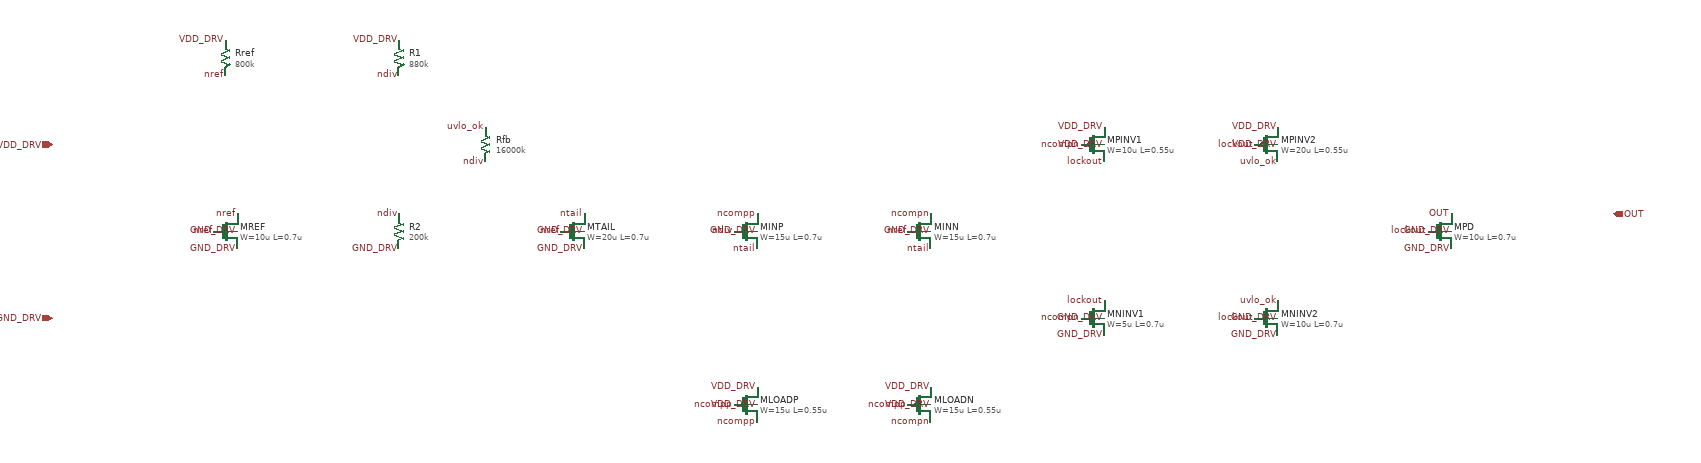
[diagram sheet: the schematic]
v {xschem version=3.4.7 file_version=1.2

* uvlo -- drive-rail undervoltage-lockout comparator/reference sub-cell
* (issue #220, spec/gate-driver.md Sec.5; parameters ratified by
* spec/decision-records/0001-block-interface-and-uvlo-parameters.md
* Decisions 4-5). Actual measured PVT numbers against those targets are
* recorded in spec/decision-records/0018-uvlo-comparator-pvt-measurement.md
* and sim/uvlo-trip-verification/records/ -- read that record before
* assuming the typ numbers below hold at every corner; they do not.
*
* Topology, exactly as decision record 0001 Decision 5 specifies: a
* resistive divider off VDD_DRV (R1/R2) compared against a diode-connected
* 6V0-corner NMOS Vt reference (XMREF), both built from nfet_06v0/pfet_06v0
* only -- no bandgap, no thin-oxide device (spec Sec.2.5, drive-rail
* domain; this cell has no VDD_LOGIC/GND_LOGIC pins at all, consistent with
* decision record 0001 Decision 5's "only VDD_DRV is monitored").
*
* Ports:
*   VDD_DRV -- 5V nominal / 6V stretch drive rail (block VDD_DRV)
*   GND_DRV -- drive rail return (block GND_DRV)
*   OUT     -- block OUT net (shared with output_stage's OUT, decision
*              record 0001 Decision 5) -- this cell actively pulls OUT low
*              (XMPD, a large nfet_06v0) whenever VDD_DRV is below the
*              rising threshold / above the falling threshold has not yet
*              been crossed, i.e. during lockout, overriding IN
*              unconditionally (XMPD's gate is driven only by this cell's
*              own comparator chain, never by IN or IN_DRV).
*
* Signal path:
*   Reference:  VDD_DRV -[Rref]-> nref -[XMREF diode-connected]-> GND_DRV
*   Divider:    VDD_DRV -[R1]-> ndiv -[R2]-> GND_DRV, with a positive-
*               feedback resistor Rfb from the buffered digital output
*               uvlo_ok back onto ndiv -- this is what creates the
*               hysteresis: Rfb effectively lowers the divider's top
*               resistance (R1||Rfb) while uvlo_ok is high (released),
*               raising ndiv for a given VDD_DRV and so requiring VDD_DRV
*               to fall further before ndiv drops back below nref (falling
*               threshold below rising threshold, matching decision record
*               0001 Decision 4's hysteresis direction). See
*               design/uvlo-comparator-sizing.md for the full derivation
*               and the measured tuning iterations.
*   Comparator: XMTAIL (current-mirrors off nref) biases a 5T differential
*               pair (XMINP/XMINN, thin... no, nfet_06v0, gates on
*               ndiv/nref) loaded by a pfet_06v0 current mirror
*               (XMLOADP/XMLOADN); ncompn is the single-ended output,
*               HIGH when ndiv > nref (VDD_DRV above the trip point).
*   Buffer:     ncompn -> INV1 (XMPINV1/XMNINV1) -> lockout (active-HIGH
*               pulldown-enable signal, HIGH during lockout) -> INV2
*               (XMPINV2/XMNINV2) -> uvlo_ok (active-HIGH "released"
*               status, drives Rfb).
*   Output:     XMPD, gate=lockout, drain=OUT, source=GND_DRV -- W=10u,
*               m=800 (effective 8000u), sized to dominate over
*               output_stage's own final push-pull stage (MP6, W=10u
*               m=500, design/output_stage.sch) so OUT is actively held
*               low regardless of what output_stage's own drive is doing.
*
* Generated by hand per xschem text format (same convention as
* design/level_shifter.sch / design/output_stage.sch), net connectivity
* verified via `xschem -x -n -s` (see PR description).
}
G {}
K {}
V {}
S {}
E {}

* --- reference generator: Rref + diode-connected XMREF ---
C {devices/res.sym} 0 -300 0 0 {name=Rref value=800k footprint=1206 device=resistor m=1}
C {devices/lab_pin.sym} 0 -330 0 0 {name=l1 lab=VDD_DRV}
C {devices/lab_pin.sym} 0 -270 0 0 {name=l2 lab=nref}
C {symbols/nfet_06v0.sym} 0 0 0 0 {name=MREF
L=0.7u
W=10u
nf=1
m=1
ad="'int((nf+1)/2) * W/nf * 0.18u'"
pd="'2*int((nf+1)/2) * (W/nf + 0.18u)'"
as="'int((nf+2)/2) * W/nf * 0.18u'"
ps="'2*int((nf+2)/2) * (W/nf + 0.18u)'"
nrd="'0.18u / W'" nrs="'0.18u / W'"
sa=0 sb=0 sd=0
model=nfet_06v0
spiceprefix=X
}
C {devices/lab_pin.sym} 20 -30 0 0 {name=l3 lab=nref}
C {devices/lab_pin.sym} -20 0 0 0 {name=l4 lab=nref}
C {devices/lab_pin.sym} 20 30 0 0 {name=l5 lab=GND_DRV}
C {devices/lab_pin.sym} 20 0 0 0 {name=l6 lab=GND_DRV}

* --- resistive divider with hysteresis feedback ---
C {devices/res.sym} 300 -300 0 0 {name=R1 value=880k footprint=1206 device=resistor m=1}
C {devices/lab_pin.sym} 300 -330 0 0 {name=l7 lab=VDD_DRV}
C {devices/lab_pin.sym} 300 -270 0 0 {name=l8 lab=ndiv}
C {devices/res.sym} 300 0 0 0 {name=R2 value=200k footprint=1206 device=resistor m=1}
C {devices/lab_pin.sym} 300 -30 0 0 {name=l9 lab=ndiv}
C {devices/lab_pin.sym} 300 30 0 0 {name=l10 lab=GND_DRV}
C {devices/res.sym} 450 -150 0 0 {name=Rfb value=16000k footprint=1206 device=resistor m=1}
C {devices/lab_pin.sym} 450 -180 0 0 {name=l11 lab=uvlo_ok}
C {devices/lab_pin.sym} 450 -120 0 0 {name=l12 lab=ndiv}

* --- tail current mirror (mirrors XMREF's bias current off nref) ---
C {symbols/nfet_06v0.sym} 600 0 0 0 {name=MTAIL
L=0.7u
W=20u
nf=1
m=1
ad="'int((nf+1)/2) * W/nf * 0.18u'"
pd="'2*int((nf+1)/2) * (W/nf + 0.18u)'"
as="'int((nf+2)/2) * W/nf * 0.18u'"
ps="'2*int((nf+2)/2) * (W/nf + 0.18u)'"
nrd="'0.18u / W'" nrs="'0.18u / W'"
sa=0 sb=0 sd=0
model=nfet_06v0
spiceprefix=X
}
C {devices/lab_pin.sym} 620 -30 0 0 {name=l13 lab=ntail}
C {devices/lab_pin.sym} 580 0 0 0 {name=l14 lab=nref}
C {devices/lab_pin.sym} 620 30 0 0 {name=l15 lab=GND_DRV}
C {devices/lab_pin.sym} 620 0 0 0 {name=l16 lab=GND_DRV}

* --- differential pair: ndiv (+) vs nref (-) ---
C {symbols/nfet_06v0.sym} 900 0 0 0 {name=MINP
L=0.7u
W=15u
nf=1
m=1
ad="'int((nf+1)/2) * W/nf * 0.18u'"
pd="'2*int((nf+1)/2) * (W/nf + 0.18u)'"
as="'int((nf+2)/2) * W/nf * 0.18u'"
ps="'2*int((nf+2)/2) * (W/nf + 0.18u)'"
nrd="'0.18u / W'" nrs="'0.18u / W'"
sa=0 sb=0 sd=0
model=nfet_06v0
spiceprefix=X
}
C {devices/lab_pin.sym} 920 -30 0 0 {name=l17 lab=ncompp}
C {devices/lab_pin.sym} 880 0 0 0 {name=l18 lab=ndiv}
C {devices/lab_pin.sym} 920 30 0 0 {name=l19 lab=ntail}
C {devices/lab_pin.sym} 920 0 0 0 {name=l20 lab=GND_DRV}
C {symbols/nfet_06v0.sym} 1200 0 0 0 {name=MINN
L=0.7u
W=15u
nf=1
m=1
ad="'int((nf+1)/2) * W/nf * 0.18u'"
pd="'2*int((nf+1)/2) * (W/nf + 0.18u)'"
as="'int((nf+2)/2) * W/nf * 0.18u'"
ps="'2*int((nf+2)/2) * (W/nf + 0.18u)'"
nrd="'0.18u / W'" nrs="'0.18u / W'"
sa=0 sb=0 sd=0
model=nfet_06v0
spiceprefix=X
}
C {devices/lab_pin.sym} 1220 -30 0 0 {name=l21 lab=ncompn}
C {devices/lab_pin.sym} 1180 0 0 0 {name=l22 lab=nref}
C {devices/lab_pin.sym} 1220 30 0 0 {name=l23 lab=ntail}
C {devices/lab_pin.sym} 1220 0 0 0 {name=l24 lab=GND_DRV}

* --- pfet current-mirror load ---
C {symbols/pfet_06v0.sym} 900 300 0 0 {name=MLOADP
L=0.55u
W=15u
nf=1
m=1
ad="'int((nf+1)/2) * W/nf * 0.18u'"
pd="'2*int((nf+1)/2) * (W/nf + 0.18u)'"
as="'int((nf+2)/2) * W/nf * 0.18u'"
ps="'2*int((nf+2)/2) * (W/nf + 0.18u)'"
nrd="'0.18u / W'" nrs="'0.18u / W'"
sa=0 sb=0 sd=0
model=pfet_06v0
spiceprefix=X
}
C {devices/lab_pin.sym} 920 330 0 0 {name=l25 lab=ncompp}
C {devices/lab_pin.sym} 880 300 0 0 {name=l26 lab=ncompp}
C {devices/lab_pin.sym} 920 270 0 0 {name=l27 lab=VDD_DRV}
C {devices/lab_pin.sym} 920 300 0 0 {name=l28 lab=VDD_DRV}
C {symbols/pfet_06v0.sym} 1200 300 0 0 {name=MLOADN
L=0.55u
W=15u
nf=1
m=1
ad="'int((nf+1)/2) * W/nf * 0.18u'"
pd="'2*int((nf+1)/2) * (W/nf + 0.18u)'"
as="'int((nf+2)/2) * W/nf * 0.18u'"
ps="'2*int((nf+2)/2) * (W/nf + 0.18u)'"
nrd="'0.18u / W'" nrs="'0.18u / W'"
sa=0 sb=0 sd=0
model=pfet_06v0
spiceprefix=X
}
C {devices/lab_pin.sym} 1220 330 0 0 {name=l29 lab=ncompn}
C {devices/lab_pin.sym} 1180 300 0 0 {name=l30 lab=ncompp}
C {devices/lab_pin.sym} 1220 270 0 0 {name=l31 lab=VDD_DRV}
C {devices/lab_pin.sym} 1220 300 0 0 {name=l32 lab=VDD_DRV}

* --- buffer stage 1: ncompn -> lockout (active-high pulldown-enable) ---
C {symbols/pfet_06v0.sym} 1500 -150 0 0 {name=MPINV1
L=0.55u
W=10u
nf=1
m=1
ad="'int((nf+1)/2) * W/nf * 0.18u'"
pd="'2*int((nf+1)/2) * (W/nf + 0.18u)'"
as="'int((nf+2)/2) * W/nf * 0.18u'"
ps="'2*int((nf+2)/2) * (W/nf + 0.18u)'"
nrd="'0.18u / W'" nrs="'0.18u / W'"
sa=0 sb=0 sd=0
model=pfet_06v0
spiceprefix=X
}
C {devices/lab_pin.sym} 1520 -120 0 0 {name=l33 lab=lockout}
C {devices/lab_pin.sym} 1480 -150 0 0 {name=l34 lab=ncompn}
C {devices/lab_pin.sym} 1520 -180 0 0 {name=l35 lab=VDD_DRV}
C {devices/lab_pin.sym} 1520 -150 0 0 {name=l36 lab=VDD_DRV}
C {symbols/nfet_06v0.sym} 1500 150 0 0 {name=MNINV1
L=0.7u
W=5u
nf=1
m=1
ad="'int((nf+1)/2) * W/nf * 0.18u'"
pd="'2*int((nf+1)/2) * (W/nf + 0.18u)'"
as="'int((nf+2)/2) * W/nf * 0.18u'"
ps="'2*int((nf+2)/2) * (W/nf + 0.18u)'"
nrd="'0.18u / W'" nrs="'0.18u / W'"
sa=0 sb=0 sd=0
model=nfet_06v0
spiceprefix=X
}
C {devices/lab_pin.sym} 1520 120 0 0 {name=l37 lab=lockout}
C {devices/lab_pin.sym} 1480 150 0 0 {name=l38 lab=ncompn}
C {devices/lab_pin.sym} 1520 180 0 0 {name=l39 lab=GND_DRV}
C {devices/lab_pin.sym} 1520 150 0 0 {name=l40 lab=GND_DRV}

* --- buffer stage 2: lockout -> uvlo_ok (drives Rfb) ---
C {symbols/pfet_06v0.sym} 1800 -150 0 0 {name=MPINV2
L=0.55u
W=20u
nf=1
m=1
ad="'int((nf+1)/2) * W/nf * 0.18u'"
pd="'2*int((nf+1)/2) * (W/nf + 0.18u)'"
as="'int((nf+2)/2) * W/nf * 0.18u'"
ps="'2*int((nf+2)/2) * (W/nf + 0.18u)'"
nrd="'0.18u / W'" nrs="'0.18u / W'"
sa=0 sb=0 sd=0
model=pfet_06v0
spiceprefix=X
}
C {devices/lab_pin.sym} 1820 -120 0 0 {name=l41 lab=uvlo_ok}
C {devices/lab_pin.sym} 1780 -150 0 0 {name=l42 lab=lockout}
C {devices/lab_pin.sym} 1820 -180 0 0 {name=l43 lab=VDD_DRV}
C {devices/lab_pin.sym} 1820 -150 0 0 {name=l44 lab=VDD_DRV}
C {symbols/nfet_06v0.sym} 1800 150 0 0 {name=MNINV2
L=0.7u
W=10u
nf=1
m=1
ad="'int((nf+1)/2) * W/nf * 0.18u'"
pd="'2*int((nf+1)/2) * (W/nf + 0.18u)'"
as="'int((nf+2)/2) * W/nf * 0.18u'"
ps="'2*int((nf+2)/2) * (W/nf + 0.18u)'"
nrd="'0.18u / W'" nrs="'0.18u / W'"
sa=0 sb=0 sd=0
model=nfet_06v0
spiceprefix=X
}
C {devices/lab_pin.sym} 1820 120 0 0 {name=l45 lab=uvlo_ok}
C {devices/lab_pin.sym} 1780 150 0 0 {name=l46 lab=lockout}
C {devices/lab_pin.sym} 1820 180 0 0 {name=l47 lab=GND_DRV}
C {devices/lab_pin.sym} 1820 150 0 0 {name=l48 lab=GND_DRV}

* --- OUT pulldown: forces OUT low during lockout, overriding IN
* unconditionally (XMPD's gate is driven only from this cell's own
* comparator chain -- IN/IN_DRV never reach this device). Sized (W=10u,
* m=800, effective 8000u) to dominate output_stage's final push-pull
* stage (design/output_stage.sch's MP6, W=10u m=500) so OUT is actively
* held low even while output_stage's own final stage is trying to drive
* it high. ---
C {symbols/nfet_06v0.sym} 2100 0 0 0 {name=MPD
L=0.7u
W=10u
nf=1
m=800
ad="'int((nf+1)/2) * W/nf * 0.18u'"
pd="'2*int((nf+1)/2) * (W/nf + 0.18u)'"
as="'int((nf+2)/2) * W/nf * 0.18u'"
ps="'2*int((nf+2)/2) * (W/nf + 0.18u)'"
nrd="'0.18u / W'" nrs="'0.18u / W'"
sa=0 sb=0 sd=0
model=nfet_06v0
spiceprefix=X
}
C {devices/lab_pin.sym} 2120 -30 0 0 {name=l49 lab=OUT}
C {devices/lab_pin.sym} 2080 0 0 0 {name=l50 lab=lockout}
C {devices/lab_pin.sym} 2120 30 0 0 {name=l51 lab=GND_DRV}
C {devices/lab_pin.sym} 2120 0 0 0 {name=l52 lab=GND_DRV}

* --- block-level ports ---
C {devices/ipin.sym} -300 -150 0 0 {name=p_vddd lab=VDD_DRV}
C {devices/ipin.sym} -300 150 0 0 {name=p_gndd lab=GND_DRV}
C {devices/opin.sym} 2400 -30 0 0 {name=p_out lab=OUT}
